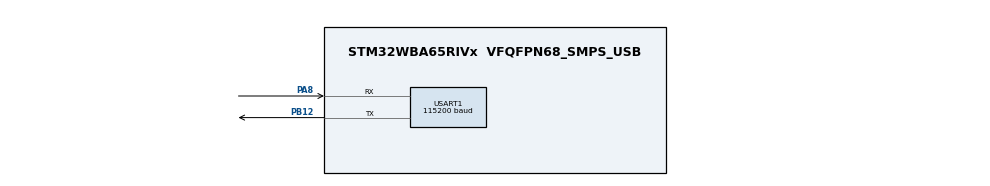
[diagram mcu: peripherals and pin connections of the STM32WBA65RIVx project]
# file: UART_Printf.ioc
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CORTEX_M33_NS.userName=CORTEX_M33
Mcu.Family=STM32WBA
Mcu.Name=STM32WBA65RIVx
Mcu.Package=VFQFPN68_SMPS_USB
NVIC.PriorityGroup=NVIC_PRIORITYGROUP_4
OSC_IN.Mode=HSE-External-Oscillator
OSC_IN.Signal=RCC_OSC_IN
OSC_OUT.Mode=HSE-External-Oscillator
OSC_OUT.Signal=RCC_OSC_OUT
PA8.GPIO_PuPd=GPIO_PULLUP
PA8.Mode=Asynchronous
PA8.Signal=USART1_RX
PB12.GPIO_PuPd=GPIO_PULLUP
PB12.Mode=Asynchronous
PB12.Signal=USART1_TX
ProjectManager.HeapSize=0x200
ProjectManager.StackSize=0x400
ProjectManager.TargetToolchain=EWARM V9.20
RCC.ADCFreq_Value=100000000
RCC.AHB5CLKDivider=DIV4
RCC.AHBFreq_Value=100000000
RCC.APB1Freq_Value=100000000
RCC.APB1TimFreq_Value=100000000
RCC.APB2Freq_Value=100000000
RCC.APB2TimFreq_Value=100000000
RCC.CortexFreq_Value=12500000
RCC.HCLKFreq_Value=100000000
RCC.HSE_VALUE=32000000
RCC.HSI_VALUE=16000000
RCC.LSE_VALUE=32768
RCC.LSI1_VALUE=32000
RCC.LSI2_VALUE=32000
RCC.PLLFRACN=4096
RCC.PLLM=2
RCC.PLLN=12
RCC.PLLSourceVirtual=RCC_PLLSOURCE_HSE
RCC.SYSCLKFreq_VALUE=100000000
RCC.SYSCLKSourceVirtual=RCC_SYSCLKSOURCE_PLLCLK
RCC.VCOOutputFreq_Value=200000000
USART1.AutoBaudRateEnableParam=UART_ADVFEATURE_AUTOBAUDRATE_DISABLE
USART1.BaudRate=115200
USART1.DMADisableonRxErrorParam=ADVFEATURE_DMA_ENABLEONRXERROR
USART1.DataInvertParam=ADVFEATURE_DATAINV_DISABLE
USART1.MSBFirstParam=ADVFEATURE_MSBFIRST_DISABLE
USART1.Mode=MODE_TX_RX
USART1.OneBitSampling=UART_ONE_BIT_SAMPLE_DISABLE
USART1.OverSampling=UART_OVERSAMPLING_16
USART1.OverrunDisableParam=ADVFEATURE_OVERRUN_ENABLE
USART1.Parity=PARITY_ODD
USART1.RxPinLevelInvertParam=ADVFEATURE_RXINV_DISABLE
USART1.StopBits=STOPBITS_1
USART1.SwapParam=ADVFEATURE_SWAP_DISABLE
USART1.TxPinLevelInvertParam=ADVFEATURE_TXINV_DISABLE
USART1.VirtualMode-Asynchronous=VM_ASYNC
USART1.WordLength=WORDLENGTH_8B
VP_CORTEX_M33_NS_VS_Hclk.Mode=Hclk_Mode
VP_ICACHE_VS_ICACHE.Mode=DirectMappedCache
VP_PWR_VS_SECSignals.Mode=Security/Privilege
board=custom

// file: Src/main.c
/* USER CODE BEGIN Header */
/**
  ******************************************************************************
  * @file    UART/UART_Printf/Src/main.c
  * @author  MCD Application Team
  * @brief   This example shows how to retarget the C library printf function
  *          to the UART.
  ******************************************************************************
  * @attention
  *
  * Copyright (c) 2024 STMicroelectronics.
  * All rights reserved.
  *
  * This software is licensed under terms that can be found in the LICENSE file
  * in the root directory of this software component.
  * If no LICENSE file comes with this software, it is provided AS-IS.
  *
  ******************************************************************************
  */
/* USER CODE END Header */
#include "main.h"

UART_HandleTypeDef huart1;

void SystemClock_Config(void);
static void MX_GPIO_Init(void);
static void MX_USART1_UART_Init(void);
static void MX_ICACHE_Init(void);
/* USER CODE BEGIN PFP */
#if defined(__ICCARM__)
__ATTRIBUTES size_t __write(int, const unsigned char *, size_t);
#endif /* __ICCARM__ */

#if defined(__ICCARM__)
/* New definition from EWARM V9, compatible with EWARM8 */
int iar_fputc(int ch);
#define PUTCHAR_PROTOTYPE int iar_fputc(int ch)
#elif defined ( __CC_ARM ) || defined(__ARMCC_VERSION)
/* ARM Compiler 5/6*/
#define PUTCHAR_PROTOTYPE int fputc(int ch, FILE *f)
#elif defined(__GNUC__)
#define PUTCHAR_PROTOTYPE int __io_putchar(int ch)
#endif /* __ICCARM__ */
/* USER CODE END PFP */

int main(void)
{

  /* USER CODE BEGIN 1 */

  /* STM32WBAxx HAL library initialization:
       - Systick timer is configured by default as source of time base, but user
             can eventually implement his proper time base source (a general purpose
             timer for example or other time source), keeping in mind that Time base
             duration should be kept 1ms since PPP_TIMEOUT_VALUEs are defined and
             handled in milliseconds basis.
       - Set NVIC Group Priority to 4
       - Low Level Initialization
     */
  /* USER CODE END 1 */

  /* MCU Configuration--------------------------------------------------------*/

  /* Reset of all peripherals, Initializes the Flash interface and the Systick. */
  HAL_Init();

  /* Configure the system clock */
  SystemClock_Config();

  /* USER CODE BEGIN SysInit */
  /* Initialize BSP Led for LD3 */
  BSP_LED_Init(LD3);
  /* USER CODE END SysInit */

  /* Initialize all configured peripherals */
  MX_GPIO_Init();
  MX_USART1_UART_Init();
  MX_ICACHE_Init();
  /* USER CODE BEGIN 2 */

  /* Output a message on Hyperterminal using printf function */
  printf("\n\r UART Printf Example: retarget the C library printf function to the UART\n\r");
  printf("** Test finished successfully. ** \n\r");
  /* USER CODE END 2 */

  /* Infinite loop */
  while (1)
  {

  }
}

void SystemClock_Config(void)
{
  RCC_OscInitTypeDef RCC_OscInitStruct = {0};
  RCC_ClkInitTypeDef RCC_ClkInitStruct = {0};

  /** Supply configuration update enable
  */
  HAL_PWREx_ConfigSupply(PWR_LDO_SUPPLY);

  /** Configure the main internal regulator output voltage
  */
  if (HAL_PWREx_ControlVoltageScaling(PWR_REGULATOR_VOLTAGE_SCALE1) != HAL_OK)
  {
    Error_Handler();
  }

  /** Initializes the CPU, AHB and APB busses clocks
  */
  RCC_OscInitStruct.OscillatorType = RCC_OSCILLATORTYPE_HSE;
  RCC_OscInitStruct.HSEState = RCC_HSE_ON;
  RCC_OscInitStruct.HSEDiv = RCC_HSE_DIV1;
  RCC_OscInitStruct.PLL1.PLLState = RCC_PLL_ON;
  RCC_OscInitStruct.PLL1.PLLSource = RCC_PLLSOURCE_HSE;
  RCC_OscInitStruct.PLL1.PLLM = 2;
  RCC_OscInitStruct.PLL1.PLLN = 12;
  RCC_OscInitStruct.PLL1.PLLP = 2;
  RCC_OscInitStruct.PLL1.PLLQ = 2;
  RCC_OscInitStruct.PLL1.PLLR = 2;
  RCC_OscInitStruct.PLL1.PLLFractional = 4096;
  if (HAL_RCC_OscConfig(&RCC_OscInitStruct) != HAL_OK)
  {
    Error_Handler();
  }

  /** Initializes the CPU, AHB and APB busses clocks
  */
  RCC_ClkInitStruct.ClockType = RCC_CLOCKTYPE_HCLK|RCC_CLOCKTYPE_SYSCLK
                              |RCC_CLOCKTYPE_PCLK1|RCC_CLOCKTYPE_PCLK2
                              |RCC_CLOCKTYPE_PCLK7|RCC_CLOCKTYPE_HCLK5;
  RCC_ClkInitStruct.SYSCLKSource = RCC_SYSCLKSOURCE_PLLCLK;
  RCC_ClkInitStruct.AHBCLKDivider = RCC_SYSCLK_DIV1;
  RCC_ClkInitStruct.APB1CLKDivider = RCC_HCLK_DIV1;
  RCC_ClkInitStruct.APB2CLKDivider = RCC_HCLK_DIV1;
  RCC_ClkInitStruct.APB7CLKDivider = RCC_HCLK_DIV1;
  RCC_ClkInitStruct.AHB5_PLL1_CLKDivider = RCC_SYSCLK_PLL1_DIV4;
  RCC_ClkInitStruct.AHB5_HSEHSI_CLKDivider = RCC_SYSCLK_HSEHSI_DIV1;

  if (HAL_RCC_ClockConfig(&RCC_ClkInitStruct, FLASH_LATENCY_3) != HAL_OK)
  {
    Error_Handler();
  }
}

static void MX_ICACHE_Init(void)
{

  /** Enable instruction cache in 1-way (direct mapped cache)
  */
  if (HAL_ICACHE_ConfigAssociativityMode(ICACHE_1WAY) != HAL_OK)
  {
    Error_Handler();
  }
  if (HAL_ICACHE_Enable() != HAL_OK)
  {
    Error_Handler();
  }

}

static void MX_USART1_UART_Init(void)
{

  huart1.Instance = USART1;
  huart1.Init.BaudRate = 115200;
  huart1.Init.WordLength = UART_WORDLENGTH_8B;
  huart1.Init.StopBits = UART_STOPBITS_1;
  huart1.Init.Parity = UART_PARITY_ODD;
  huart1.Init.Mode = UART_MODE_TX_RX;
  huart1.Init.HwFlowCtl = UART_HWCONTROL_NONE;
  huart1.Init.OverSampling = UART_OVERSAMPLING_16;
  huart1.Init.OneBitSampling = UART_ONE_BIT_SAMPLE_DISABLE;
  huart1.Init.ClockPrescaler = UART_PRESCALER_DIV1;
  huart1.AdvancedInit.AdvFeatureInit = UART_ADVFEATURE_NO_INIT;
  if (HAL_UART_Init(&huart1) != HAL_OK)
  {
    Error_Handler();
  }
  if (HAL_UARTEx_SetTxFifoThreshold(&huart1, UART_TXFIFO_THRESHOLD_1_8) != HAL_OK)
  {
    Error_Handler();
  }
  if (HAL_UARTEx_SetRxFifoThreshold(&huart1, UART_RXFIFO_THRESHOLD_1_8) != HAL_OK)
  {
    Error_Handler();
  }
  if (HAL_UARTEx_DisableFifoMode(&huart1) != HAL_OK)
  {
    Error_Handler();
  }

}

static void MX_GPIO_Init(void)
{

  /* GPIO Ports Clock Enable */
  __HAL_RCC_GPIOB_CLK_ENABLE();
  __HAL_RCC_GPIOA_CLK_ENABLE();

}

/* USER CODE BEGIN 4 */
/**
  * @brief  Retargets the C library printf function to the USART.
  * @param  None
  * @retval None
  */
PUTCHAR_PROTOTYPE
{
  /* Place your implementation of fputc here */
  /* e.g. write a character to the USART1 and Loop until the end of transmission */
  HAL_UART_Transmit(&huart1, (uint8_t *)&ch, 1, 0xFFFF);

  return ch;
}

#if defined(__ICCARM__)
size_t __write(int file, unsigned char const *ptr, size_t len)
{
  size_t idx;
  unsigned char const *pdata = ptr;

  for (idx = 0; idx < len; idx++)
  {
    iar_fputc((int)*pdata);
    pdata++;
  }
  return len;
}
#endif /* __ICCARM__ */

/* USER CODE END 4 */

void Error_Handler(void)
{
  /* USER CODE BEGIN Error_Handler_Debug */
  /* User can add his own implementation to report the HAL error return state */
  /* Turn LD3 on */
  BSP_LED_On(LD3);
  while (1);
  /* USER CODE END Error_Handler_Debug */
}
